VERSION 5.7 ;
  NOWIREEXTENSIONATPIN ON ;
  DIVIDERCHAR "/" ;
  BUSBITCHARS "[]" ;
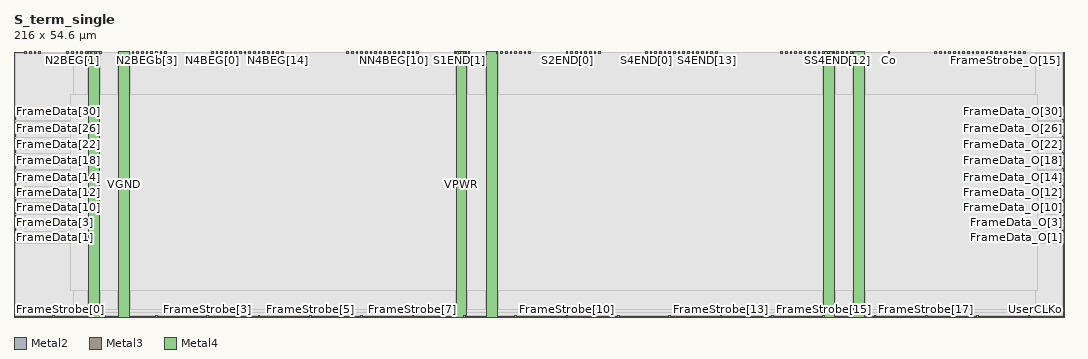
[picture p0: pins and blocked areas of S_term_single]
MACRO S_term_single
  CLASS BLOCK ;
  FOREIGN S_term_single ;
  ORIGIN 0.000 0.000 ;
  SIZE 216.000 BY 54.600 ;
  PIN Co
    DIRECTION OUTPUT ;
    USE SIGNAL ;
    ANTENNADIFFAREA 2.314600 ;
    PORT
      LAYER Metal2 ;
        RECT 179.800 54.200 180.200 54.600 ;
    END
  END Co
  PIN FrameData[0]
    DIRECTION INPUT ;
    USE SIGNAL ;
    ANTENNAGATEAREA 0.180700 ;
    ANTENNADIFFAREA 2.015400 ;
    PORT
      LAYER Metal3 ;
        RECT 0.000 15.340 0.400 15.740 ;
    END
  END FrameData[0]
  PIN FrameData[10]
    DIRECTION INPUT ;
    USE SIGNAL ;
    ANTENNAGATEAREA 0.180700 ;
    ANTENNADIFFAREA 2.015400 ;
    PORT
      LAYER Metal3 ;
        RECT 0.000 23.740 0.400 24.140 ;
    END
  END FrameData[10]
  PIN FrameData[11]
    DIRECTION INPUT ;
    USE SIGNAL ;
    ANTENNAGATEAREA 0.180700 ;
    ANTENNADIFFAREA 2.015400 ;
    PORT
      LAYER Metal3 ;
        RECT 0.000 24.580 0.400 24.980 ;
    END
  END FrameData[11]
  PIN FrameData[12]
    DIRECTION INPUT ;
    USE SIGNAL ;
    ANTENNAGATEAREA 0.180700 ;
    ANTENNADIFFAREA 2.015400 ;
    PORT
      LAYER Metal3 ;
        RECT 0.000 25.420 0.400 25.820 ;
    END
  END FrameData[12]
  PIN FrameData[13]
    DIRECTION INPUT ;
    USE SIGNAL ;
    ANTENNAGATEAREA 0.180700 ;
    ANTENNADIFFAREA 2.015400 ;
    PORT
      LAYER Metal3 ;
        RECT 0.000 26.260 0.400 26.660 ;
    END
  END FrameData[13]
  PIN FrameData[14]
    DIRECTION INPUT ;
    USE SIGNAL ;
    ANTENNAGATEAREA 0.180700 ;
    ANTENNADIFFAREA 2.015400 ;
    PORT
      LAYER Metal3 ;
        RECT 0.000 27.100 0.400 27.500 ;
    END
  END FrameData[14]
  PIN FrameData[15]
    DIRECTION INPUT ;
    USE SIGNAL ;
    ANTENNAGATEAREA 0.180700 ;
    ANTENNADIFFAREA 2.015400 ;
    PORT
      LAYER Metal3 ;
        RECT 0.000 27.940 0.400 28.340 ;
    END
  END FrameData[15]
  PIN FrameData[16]
    DIRECTION INPUT ;
    USE SIGNAL ;
    ANTENNAGATEAREA 0.180700 ;
    ANTENNADIFFAREA 2.015400 ;
    PORT
      LAYER Metal3 ;
        RECT 0.000 28.780 0.400 29.180 ;
    END
  END FrameData[16]
  PIN FrameData[17]
    DIRECTION INPUT ;
    USE SIGNAL ;
    ANTENNAGATEAREA 0.180700 ;
    ANTENNADIFFAREA 2.015400 ;
    PORT
      LAYER Metal3 ;
        RECT 0.000 29.620 0.400 30.020 ;
    END
  END FrameData[17]
  PIN FrameData[18]
    DIRECTION INPUT ;
    USE SIGNAL ;
    ANTENNAGATEAREA 0.180700 ;
    ANTENNADIFFAREA 2.015400 ;
    PORT
      LAYER Metal3 ;
        RECT 0.000 30.460 0.400 30.860 ;
    END
  END FrameData[18]
  PIN FrameData[19]
    DIRECTION INPUT ;
    USE SIGNAL ;
    ANTENNAGATEAREA 0.180700 ;
    ANTENNADIFFAREA 2.015400 ;
    PORT
      LAYER Metal3 ;
        RECT 0.000 31.300 0.400 31.700 ;
    END
  END FrameData[19]
  PIN FrameData[1]
    DIRECTION INPUT ;
    USE SIGNAL ;
    ANTENNAGATEAREA 0.180700 ;
    ANTENNADIFFAREA 2.015400 ;
    PORT
      LAYER Metal3 ;
        RECT 0.000 16.180 0.400 16.580 ;
    END
  END FrameData[1]
  PIN FrameData[20]
    DIRECTION INPUT ;
    USE SIGNAL ;
    ANTENNAGATEAREA 0.180700 ;
    ANTENNADIFFAREA 2.015400 ;
    PORT
      LAYER Metal3 ;
        RECT 0.000 32.140 0.400 32.540 ;
    END
  END FrameData[20]
  PIN FrameData[21]
    DIRECTION INPUT ;
    USE SIGNAL ;
    ANTENNAGATEAREA 0.180700 ;
    ANTENNADIFFAREA 2.015400 ;
    PORT
      LAYER Metal3 ;
        RECT 0.000 32.980 0.400 33.380 ;
    END
  END FrameData[21]
  PIN FrameData[22]
    DIRECTION INPUT ;
    USE SIGNAL ;
    ANTENNAGATEAREA 0.180700 ;
    ANTENNADIFFAREA 2.015400 ;
    PORT
      LAYER Metal3 ;
        RECT 0.000 33.820 0.400 34.220 ;
    END
  END FrameData[22]
  PIN FrameData[23]
    DIRECTION INPUT ;
    USE SIGNAL ;
    ANTENNAGATEAREA 0.180700 ;
    ANTENNADIFFAREA 2.015400 ;
    PORT
      LAYER Metal3 ;
        RECT 0.000 34.660 0.400 35.060 ;
    END
  END FrameData[23]
  PIN FrameData[24]
    DIRECTION INPUT ;
    USE SIGNAL ;
    ANTENNAGATEAREA 0.180700 ;
    ANTENNADIFFAREA 2.015400 ;
    PORT
      LAYER Metal3 ;
        RECT 0.000 35.500 0.400 35.900 ;
    END
  END FrameData[24]
  PIN FrameData[25]
    DIRECTION INPUT ;
    USE SIGNAL ;
    ANTENNAGATEAREA 0.180700 ;
    ANTENNADIFFAREA 2.015400 ;
    PORT
      LAYER Metal3 ;
        RECT 0.000 36.340 0.400 36.740 ;
    END
  END FrameData[25]
  PIN FrameData[26]
    DIRECTION INPUT ;
    USE SIGNAL ;
    ANTENNAGATEAREA 0.180700 ;
    ANTENNADIFFAREA 2.015400 ;
    PORT
      LAYER Metal3 ;
        RECT 0.000 37.180 0.400 37.580 ;
    END
  END FrameData[26]
  PIN FrameData[27]
    DIRECTION INPUT ;
    USE SIGNAL ;
    ANTENNAGATEAREA 0.180700 ;
    ANTENNADIFFAREA 2.015400 ;
    PORT
      LAYER Metal3 ;
        RECT 0.000 38.020 0.400 38.420 ;
    END
  END FrameData[27]
  PIN FrameData[28]
    DIRECTION INPUT ;
    USE SIGNAL ;
    ANTENNAGATEAREA 0.180700 ;
    ANTENNADIFFAREA 2.015400 ;
    PORT
      LAYER Metal3 ;
        RECT 0.000 38.860 0.400 39.260 ;
    END
  END FrameData[28]
  PIN FrameData[29]
    DIRECTION INPUT ;
    USE SIGNAL ;
    ANTENNAGATEAREA 0.180700 ;
    ANTENNADIFFAREA 2.015400 ;
    PORT
      LAYER Metal3 ;
        RECT 0.000 39.700 0.400 40.100 ;
    END
  END FrameData[29]
  PIN FrameData[2]
    DIRECTION INPUT ;
    USE SIGNAL ;
    ANTENNAGATEAREA 0.180700 ;
    ANTENNADIFFAREA 2.015400 ;
    PORT
      LAYER Metal3 ;
        RECT 0.000 17.020 0.400 17.420 ;
    END
  END FrameData[2]
  PIN FrameData[30]
    DIRECTION INPUT ;
    USE SIGNAL ;
    ANTENNAGATEAREA 0.180700 ;
    ANTENNADIFFAREA 2.015400 ;
    PORT
      LAYER Metal3 ;
        RECT 0.000 40.540 0.400 40.940 ;
    END
  END FrameData[30]
  PIN FrameData[31]
    DIRECTION INPUT ;
    USE SIGNAL ;
    ANTENNAGATEAREA 0.180700 ;
    ANTENNADIFFAREA 2.015400 ;
    PORT
      LAYER Metal3 ;
        RECT 0.000 41.380 0.400 41.780 ;
    END
  END FrameData[31]
  PIN FrameData[3]
    DIRECTION INPUT ;
    USE SIGNAL ;
    ANTENNAGATEAREA 0.180700 ;
    ANTENNADIFFAREA 2.015400 ;
    PORT
      LAYER Metal3 ;
        RECT 0.000 17.860 0.400 18.260 ;
    END
  END FrameData[3]
  PIN FrameData[4]
    DIRECTION INPUT ;
    USE SIGNAL ;
    ANTENNAGATEAREA 0.180700 ;
    ANTENNADIFFAREA 2.015400 ;
    PORT
      LAYER Metal3 ;
        RECT 0.000 18.700 0.400 19.100 ;
    END
  END FrameData[4]
  PIN FrameData[5]
    DIRECTION INPUT ;
    USE SIGNAL ;
    ANTENNAGATEAREA 0.180700 ;
    ANTENNADIFFAREA 2.015400 ;
    PORT
      LAYER Metal3 ;
        RECT 0.000 19.540 0.400 19.940 ;
    END
  END FrameData[5]
  PIN FrameData[6]
    DIRECTION INPUT ;
    USE SIGNAL ;
    ANTENNAGATEAREA 0.180700 ;
    ANTENNADIFFAREA 2.015400 ;
    PORT
      LAYER Metal3 ;
        RECT 0.000 20.380 0.400 20.780 ;
    END
  END FrameData[6]
  PIN FrameData[7]
    DIRECTION INPUT ;
    USE SIGNAL ;
    ANTENNAGATEAREA 0.180700 ;
    ANTENNADIFFAREA 2.015400 ;
    PORT
      LAYER Metal3 ;
        RECT 0.000 21.220 0.400 21.620 ;
    END
  END FrameData[7]
  PIN FrameData[8]
    DIRECTION INPUT ;
    USE SIGNAL ;
    ANTENNAGATEAREA 0.180700 ;
    ANTENNADIFFAREA 2.015400 ;
    PORT
      LAYER Metal3 ;
        RECT 0.000 22.060 0.400 22.460 ;
    END
  END FrameData[8]
  PIN FrameData[9]
    DIRECTION INPUT ;
    USE SIGNAL ;
    ANTENNAGATEAREA 0.180700 ;
    ANTENNADIFFAREA 2.015400 ;
    PORT
      LAYER Metal3 ;
        RECT 0.000 22.900 0.400 23.300 ;
    END
  END FrameData[9]
  PIN FrameData_O[0]
    DIRECTION OUTPUT ;
    USE SIGNAL ;
    ANTENNADIFFAREA 2.724000 ;
    PORT
      LAYER Metal3 ;
        RECT 215.600 15.340 216.000 15.740 ;
    END
  END FrameData_O[0]
  PIN FrameData_O[10]
    DIRECTION OUTPUT ;
    USE SIGNAL ;
    ANTENNADIFFAREA 2.724000 ;
    PORT
      LAYER Metal3 ;
        RECT 215.600 23.740 216.000 24.140 ;
    END
  END FrameData_O[10]
  PIN FrameData_O[11]
    DIRECTION OUTPUT ;
    USE SIGNAL ;
    ANTENNADIFFAREA 2.724000 ;
    PORT
      LAYER Metal3 ;
        RECT 215.600 24.580 216.000 24.980 ;
    END
  END FrameData_O[11]
  PIN FrameData_O[12]
    DIRECTION OUTPUT ;
    USE SIGNAL ;
    ANTENNADIFFAREA 2.724000 ;
    PORT
      LAYER Metal3 ;
        RECT 215.600 25.420 216.000 25.820 ;
    END
  END FrameData_O[12]
  PIN FrameData_O[13]
    DIRECTION OUTPUT ;
    USE SIGNAL ;
    ANTENNADIFFAREA 2.724000 ;
    PORT
      LAYER Metal3 ;
        RECT 215.600 26.260 216.000 26.660 ;
    END
  END FrameData_O[13]
  PIN FrameData_O[14]
    DIRECTION OUTPUT ;
    USE SIGNAL ;
    ANTENNADIFFAREA 2.724000 ;
    PORT
      LAYER Metal3 ;
        RECT 215.600 27.100 216.000 27.500 ;
    END
  END FrameData_O[14]
  PIN FrameData_O[15]
    DIRECTION OUTPUT ;
    USE SIGNAL ;
    ANTENNADIFFAREA 2.724000 ;
    PORT
      LAYER Metal3 ;
        RECT 215.600 27.940 216.000 28.340 ;
    END
  END FrameData_O[15]
  PIN FrameData_O[16]
    DIRECTION OUTPUT ;
    USE SIGNAL ;
    ANTENNADIFFAREA 2.724000 ;
    PORT
      LAYER Metal3 ;
        RECT 215.600 28.780 216.000 29.180 ;
    END
  END FrameData_O[16]
  PIN FrameData_O[17]
    DIRECTION OUTPUT ;
    USE SIGNAL ;
    ANTENNADIFFAREA 2.724000 ;
    PORT
      LAYER Metal3 ;
        RECT 215.600 29.620 216.000 30.020 ;
    END
  END FrameData_O[17]
  PIN FrameData_O[18]
    DIRECTION OUTPUT ;
    USE SIGNAL ;
    ANTENNADIFFAREA 2.724000 ;
    PORT
      LAYER Metal3 ;
        RECT 215.600 30.460 216.000 30.860 ;
    END
  END FrameData_O[18]
  PIN FrameData_O[19]
    DIRECTION OUTPUT ;
    USE SIGNAL ;
    ANTENNADIFFAREA 2.724000 ;
    PORT
      LAYER Metal3 ;
        RECT 215.600 31.300 216.000 31.700 ;
    END
  END FrameData_O[19]
  PIN FrameData_O[1]
    DIRECTION OUTPUT ;
    USE SIGNAL ;
    ANTENNADIFFAREA 2.724000 ;
    PORT
      LAYER Metal3 ;
        RECT 215.600 16.180 216.000 16.580 ;
    END
  END FrameData_O[1]
  PIN FrameData_O[20]
    DIRECTION OUTPUT ;
    USE SIGNAL ;
    ANTENNADIFFAREA 2.724000 ;
    PORT
      LAYER Metal3 ;
        RECT 215.600 32.140 216.000 32.540 ;
    END
  END FrameData_O[20]
  PIN FrameData_O[21]
    DIRECTION OUTPUT ;
    USE SIGNAL ;
    ANTENNADIFFAREA 2.724000 ;
    PORT
      LAYER Metal3 ;
        RECT 215.600 32.980 216.000 33.380 ;
    END
  END FrameData_O[21]
  PIN FrameData_O[22]
    DIRECTION OUTPUT ;
    USE SIGNAL ;
    ANTENNADIFFAREA 2.724000 ;
    PORT
      LAYER Metal3 ;
        RECT 215.600 33.820 216.000 34.220 ;
    END
  END FrameData_O[22]
  PIN FrameData_O[23]
    DIRECTION OUTPUT ;
    USE SIGNAL ;
    ANTENNADIFFAREA 2.724000 ;
    PORT
      LAYER Metal3 ;
        RECT 215.600 34.660 216.000 35.060 ;
    END
  END FrameData_O[23]
  PIN FrameData_O[24]
    DIRECTION OUTPUT ;
    USE SIGNAL ;
    ANTENNADIFFAREA 2.724000 ;
    PORT
      LAYER Metal3 ;
        RECT 215.600 35.500 216.000 35.900 ;
    END
  END FrameData_O[24]
  PIN FrameData_O[25]
    DIRECTION OUTPUT ;
    USE SIGNAL ;
    ANTENNADIFFAREA 2.724000 ;
    PORT
      LAYER Metal3 ;
        RECT 215.600 36.340 216.000 36.740 ;
    END
  END FrameData_O[25]
  PIN FrameData_O[26]
    DIRECTION OUTPUT ;
    USE SIGNAL ;
    ANTENNADIFFAREA 2.724000 ;
    PORT
      LAYER Metal3 ;
        RECT 215.600 37.180 216.000 37.580 ;
    END
  END FrameData_O[26]
  PIN FrameData_O[27]
    DIRECTION OUTPUT ;
    USE SIGNAL ;
    ANTENNADIFFAREA 2.724000 ;
    PORT
      LAYER Metal3 ;
        RECT 215.600 38.020 216.000 38.420 ;
    END
  END FrameData_O[27]
  PIN FrameData_O[28]
    DIRECTION OUTPUT ;
    USE SIGNAL ;
    ANTENNADIFFAREA 2.724000 ;
    PORT
      LAYER Metal3 ;
        RECT 215.600 38.860 216.000 39.260 ;
    END
  END FrameData_O[28]
  PIN FrameData_O[29]
    DIRECTION OUTPUT ;
    USE SIGNAL ;
    ANTENNADIFFAREA 2.724000 ;
    PORT
      LAYER Metal3 ;
        RECT 215.600 39.700 216.000 40.100 ;
    END
  END FrameData_O[29]
  PIN FrameData_O[2]
    DIRECTION OUTPUT ;
    USE SIGNAL ;
    ANTENNADIFFAREA 2.724000 ;
    PORT
      LAYER Metal3 ;
        RECT 215.600 17.020 216.000 17.420 ;
    END
  END FrameData_O[2]
  PIN FrameData_O[30]
    DIRECTION OUTPUT ;
    USE SIGNAL ;
    ANTENNADIFFAREA 2.724000 ;
    PORT
      LAYER Metal3 ;
        RECT 215.600 40.540 216.000 40.940 ;
    END
  END FrameData_O[30]
  PIN FrameData_O[31]
    DIRECTION OUTPUT ;
    USE SIGNAL ;
    ANTENNADIFFAREA 2.724000 ;
    PORT
      LAYER Metal3 ;
        RECT 215.600 41.380 216.000 41.780 ;
    END
  END FrameData_O[31]
  PIN FrameData_O[3]
    DIRECTION OUTPUT ;
    USE SIGNAL ;
    ANTENNADIFFAREA 2.724000 ;
    PORT
      LAYER Metal3 ;
        RECT 215.600 17.860 216.000 18.260 ;
    END
  END FrameData_O[3]
  PIN FrameData_O[4]
    DIRECTION OUTPUT ;
    USE SIGNAL ;
    ANTENNADIFFAREA 2.724000 ;
    PORT
      LAYER Metal3 ;
        RECT 215.600 18.700 216.000 19.100 ;
    END
  END FrameData_O[4]
  PIN FrameData_O[5]
    DIRECTION OUTPUT ;
    USE SIGNAL ;
    ANTENNADIFFAREA 2.724000 ;
    PORT
      LAYER Metal3 ;
        RECT 215.600 19.540 216.000 19.940 ;
    END
  END FrameData_O[5]
  PIN FrameData_O[6]
    DIRECTION OUTPUT ;
    USE SIGNAL ;
    ANTENNADIFFAREA 2.724000 ;
    PORT
      LAYER Metal3 ;
        RECT 215.600 20.380 216.000 20.780 ;
    END
  END FrameData_O[6]
  PIN FrameData_O[7]
    DIRECTION OUTPUT ;
    USE SIGNAL ;
    ANTENNADIFFAREA 2.724000 ;
    PORT
      LAYER Metal3 ;
        RECT 215.600 21.220 216.000 21.620 ;
    END
  END FrameData_O[7]
  PIN FrameData_O[8]
    DIRECTION OUTPUT ;
    USE SIGNAL ;
    ANTENNADIFFAREA 2.724000 ;
    PORT
      LAYER Metal3 ;
        RECT 215.600 22.060 216.000 22.460 ;
    END
  END FrameData_O[8]
  PIN FrameData_O[9]
    DIRECTION OUTPUT ;
    USE SIGNAL ;
    ANTENNADIFFAREA 2.724000 ;
    PORT
      LAYER Metal3 ;
        RECT 215.600 22.900 216.000 23.300 ;
    END
  END FrameData_O[9]
  PIN FrameStrobe[0]
    DIRECTION INPUT ;
    USE SIGNAL ;
    ANTENNAGATEAREA 0.180700 ;
    ANTENNADIFFAREA 2.015400 ;
    PORT
      LAYER Metal2 ;
        RECT 7.960 0.000 8.360 0.400 ;
    END
  END FrameStrobe[0]
  PIN FrameStrobe[10]
    DIRECTION INPUT ;
    USE SIGNAL ;
    ANTENNAGATEAREA 0.180700 ;
    ANTENNADIFFAREA 2.015400 ;
    PORT
      LAYER Metal2 ;
        RECT 113.560 0.000 113.960 0.400 ;
    END
  END FrameStrobe[10]
  PIN FrameStrobe[11]
    DIRECTION INPUT ;
    USE SIGNAL ;
    ANTENNAGATEAREA 0.180700 ;
    ANTENNADIFFAREA 2.015400 ;
    PORT
      LAYER Metal2 ;
        RECT 124.120 0.000 124.520 0.400 ;
    END
  END FrameStrobe[11]
  PIN FrameStrobe[12]
    DIRECTION INPUT ;
    USE SIGNAL ;
    ANTENNAGATEAREA 0.180700 ;
    ANTENNADIFFAREA 2.015400 ;
    PORT
      LAYER Metal2 ;
        RECT 134.680 0.000 135.080 0.400 ;
    END
  END FrameStrobe[12]
  PIN FrameStrobe[13]
    DIRECTION INPUT ;
    USE SIGNAL ;
    ANTENNAGATEAREA 0.180700 ;
    ANTENNADIFFAREA 2.015400 ;
    PORT
      LAYER Metal2 ;
        RECT 145.240 0.000 145.640 0.400 ;
    END
  END FrameStrobe[13]
  PIN FrameStrobe[14]
    DIRECTION INPUT ;
    USE SIGNAL ;
    ANTENNAGATEAREA 0.180700 ;
    ANTENNADIFFAREA 2.015400 ;
    PORT
      LAYER Metal2 ;
        RECT 155.800 0.000 156.200 0.400 ;
    END
  END FrameStrobe[14]
  PIN FrameStrobe[15]
    DIRECTION INPUT ;
    USE SIGNAL ;
    ANTENNAGATEAREA 0.180700 ;
    ANTENNADIFFAREA 2.015400 ;
    PORT
      LAYER Metal2 ;
        RECT 166.360 0.000 166.760 0.400 ;
    END
  END FrameStrobe[15]
  PIN FrameStrobe[16]
    DIRECTION INPUT ;
    USE SIGNAL ;
    ANTENNAGATEAREA 0.180700 ;
    ANTENNADIFFAREA 2.015400 ;
    PORT
      LAYER Metal2 ;
        RECT 176.920 0.000 177.320 0.400 ;
    END
  END FrameStrobe[16]
  PIN FrameStrobe[17]
    DIRECTION INPUT ;
    USE SIGNAL ;
    ANTENNAGATEAREA 0.180700 ;
    ANTENNADIFFAREA 2.015400 ;
    PORT
      LAYER Metal2 ;
        RECT 187.480 0.000 187.880 0.400 ;
    END
  END FrameStrobe[17]
  PIN FrameStrobe[18]
    DIRECTION INPUT ;
    USE SIGNAL ;
    ANTENNAGATEAREA 0.180700 ;
    ANTENNADIFFAREA 2.015400 ;
    PORT
      LAYER Metal2 ;
        RECT 198.040 0.000 198.440 0.400 ;
    END
  END FrameStrobe[18]
  PIN FrameStrobe[19]
    DIRECTION INPUT ;
    USE SIGNAL ;
    ANTENNAGATEAREA 0.180700 ;
    ANTENNADIFFAREA 2.015400 ;
    PORT
      LAYER Metal2 ;
        RECT 208.600 0.000 209.000 0.400 ;
    END
  END FrameStrobe[19]
  PIN FrameStrobe[1]
    DIRECTION INPUT ;
    USE SIGNAL ;
    ANTENNAGATEAREA 0.180700 ;
    ANTENNADIFFAREA 2.015400 ;
    PORT
      LAYER Metal2 ;
        RECT 18.520 0.000 18.920 0.400 ;
    END
  END FrameStrobe[1]
  PIN FrameStrobe[2]
    DIRECTION INPUT ;
    USE SIGNAL ;
    ANTENNAGATEAREA 0.180700 ;
    ANTENNADIFFAREA 2.015400 ;
    PORT
      LAYER Metal2 ;
        RECT 29.080 0.000 29.480 0.400 ;
    END
  END FrameStrobe[2]
  PIN FrameStrobe[3]
    DIRECTION INPUT ;
    USE SIGNAL ;
    ANTENNAGATEAREA 0.180700 ;
    ANTENNADIFFAREA 2.015400 ;
    PORT
      LAYER Metal2 ;
        RECT 39.640 0.000 40.040 0.400 ;
    END
  END FrameStrobe[3]
  PIN FrameStrobe[4]
    DIRECTION INPUT ;
    USE SIGNAL ;
    ANTENNAGATEAREA 0.180700 ;
    ANTENNADIFFAREA 2.015400 ;
    PORT
      LAYER Metal2 ;
        RECT 50.200 0.000 50.600 0.400 ;
    END
  END FrameStrobe[4]
  PIN FrameStrobe[5]
    DIRECTION INPUT ;
    USE SIGNAL ;
    ANTENNAGATEAREA 0.180700 ;
    ANTENNADIFFAREA 2.015400 ;
    PORT
      LAYER Metal2 ;
        RECT 60.760 0.000 61.160 0.400 ;
    END
  END FrameStrobe[5]
  PIN FrameStrobe[6]
    DIRECTION INPUT ;
    USE SIGNAL ;
    ANTENNAGATEAREA 0.180700 ;
    ANTENNADIFFAREA 2.015400 ;
    PORT
      LAYER Metal2 ;
        RECT 71.320 0.000 71.720 0.400 ;
    END
  END FrameStrobe[6]
  PIN FrameStrobe[7]
    DIRECTION INPUT ;
    USE SIGNAL ;
    ANTENNAGATEAREA 0.180700 ;
    ANTENNADIFFAREA 2.015400 ;
    PORT
      LAYER Metal2 ;
        RECT 81.880 0.000 82.280 0.400 ;
    END
  END FrameStrobe[7]
  PIN FrameStrobe[8]
    DIRECTION INPUT ;
    USE SIGNAL ;
    ANTENNAGATEAREA 0.180700 ;
    ANTENNADIFFAREA 2.015400 ;
    PORT
      LAYER Metal2 ;
        RECT 92.440 0.000 92.840 0.400 ;
    END
  END FrameStrobe[8]
  PIN FrameStrobe[9]
    DIRECTION INPUT ;
    USE SIGNAL ;
    ANTENNAGATEAREA 0.180700 ;
    ANTENNADIFFAREA 2.015400 ;
    PORT
      LAYER Metal2 ;
        RECT 103.000 0.000 103.400 0.400 ;
    END
  END FrameStrobe[9]
  PIN FrameStrobe_O[0]
    DIRECTION OUTPUT ;
    USE SIGNAL ;
    ANTENNADIFFAREA 2.724000 ;
    PORT
      LAYER Metal2 ;
        RECT 189.400 54.200 189.800 54.600 ;
    END
  END FrameStrobe_O[0]
  PIN FrameStrobe_O[10]
    DIRECTION OUTPUT ;
    USE SIGNAL ;
    ANTENNADIFFAREA 2.724000 ;
    PORT
      LAYER Metal2 ;
        RECT 199.000 54.200 199.400 54.600 ;
    END
  END FrameStrobe_O[10]
  PIN FrameStrobe_O[11]
    DIRECTION OUTPUT ;
    USE SIGNAL ;
    ANTENNADIFFAREA 2.724000 ;
    PORT
      LAYER Metal2 ;
        RECT 199.960 54.200 200.360 54.600 ;
    END
  END FrameStrobe_O[11]
  PIN FrameStrobe_O[12]
    DIRECTION OUTPUT ;
    USE SIGNAL ;
    ANTENNADIFFAREA 2.724000 ;
    PORT
      LAYER Metal2 ;
        RECT 200.920 54.200 201.320 54.600 ;
    END
  END FrameStrobe_O[12]
  PIN FrameStrobe_O[13]
    DIRECTION OUTPUT ;
    USE SIGNAL ;
    ANTENNADIFFAREA 2.724000 ;
    PORT
      LAYER Metal2 ;
        RECT 201.880 54.200 202.280 54.600 ;
    END
  END FrameStrobe_O[13]
  PIN FrameStrobe_O[14]
    DIRECTION OUTPUT ;
    USE SIGNAL ;
    ANTENNADIFFAREA 2.724000 ;
    PORT
      LAYER Metal2 ;
        RECT 202.840 54.200 203.240 54.600 ;
    END
  END FrameStrobe_O[14]
  PIN FrameStrobe_O[15]
    DIRECTION OUTPUT ;
    USE SIGNAL ;
    ANTENNADIFFAREA 2.724000 ;
    PORT
      LAYER Metal2 ;
        RECT 203.800 54.200 204.200 54.600 ;
    END
  END FrameStrobe_O[15]
  PIN FrameStrobe_O[16]
    DIRECTION OUTPUT ;
    USE SIGNAL ;
    ANTENNADIFFAREA 2.724000 ;
    PORT
      LAYER Metal2 ;
        RECT 204.760 54.200 205.160 54.600 ;
    END
  END FrameStrobe_O[16]
  PIN FrameStrobe_O[17]
    DIRECTION OUTPUT ;
    USE SIGNAL ;
    ANTENNADIFFAREA 2.724000 ;
    PORT
      LAYER Metal2 ;
        RECT 205.720 54.200 206.120 54.600 ;
    END
  END FrameStrobe_O[17]
  PIN FrameStrobe_O[18]
    DIRECTION OUTPUT ;
    USE SIGNAL ;
    ANTENNADIFFAREA 2.724000 ;
    PORT
      LAYER Metal2 ;
        RECT 206.680 54.200 207.080 54.600 ;
    END
  END FrameStrobe_O[18]
  PIN FrameStrobe_O[19]
    DIRECTION OUTPUT ;
    USE SIGNAL ;
    ANTENNADIFFAREA 2.724000 ;
    PORT
      LAYER Metal2 ;
        RECT 207.640 54.200 208.040 54.600 ;
    END
  END FrameStrobe_O[19]
  PIN FrameStrobe_O[1]
    DIRECTION OUTPUT ;
    USE SIGNAL ;
    ANTENNADIFFAREA 2.724000 ;
    PORT
      LAYER Metal2 ;
        RECT 190.360 54.200 190.760 54.600 ;
    END
  END FrameStrobe_O[1]
  PIN FrameStrobe_O[2]
    DIRECTION OUTPUT ;
    USE SIGNAL ;
    ANTENNADIFFAREA 2.724000 ;
    PORT
      LAYER Metal2 ;
        RECT 191.320 54.200 191.720 54.600 ;
    END
  END FrameStrobe_O[2]
  PIN FrameStrobe_O[3]
    DIRECTION OUTPUT ;
    USE SIGNAL ;
    ANTENNADIFFAREA 2.724000 ;
    PORT
      LAYER Metal2 ;
        RECT 192.280 54.200 192.680 54.600 ;
    END
  END FrameStrobe_O[3]
  PIN FrameStrobe_O[4]
    DIRECTION OUTPUT ;
    USE SIGNAL ;
    ANTENNADIFFAREA 2.724000 ;
    PORT
      LAYER Metal2 ;
        RECT 193.240 54.200 193.640 54.600 ;
    END
  END FrameStrobe_O[4]
  PIN FrameStrobe_O[5]
    DIRECTION OUTPUT ;
    USE SIGNAL ;
    ANTENNADIFFAREA 2.724000 ;
    PORT
      LAYER Metal2 ;
        RECT 194.200 54.200 194.600 54.600 ;
    END
  END FrameStrobe_O[5]
  PIN FrameStrobe_O[6]
    DIRECTION OUTPUT ;
    USE SIGNAL ;
    ANTENNADIFFAREA 2.724000 ;
    PORT
      LAYER Metal2 ;
        RECT 195.160 54.200 195.560 54.600 ;
    END
  END FrameStrobe_O[6]
  PIN FrameStrobe_O[7]
    DIRECTION OUTPUT ;
    USE SIGNAL ;
    ANTENNADIFFAREA 2.724000 ;
    PORT
      LAYER Metal2 ;
        RECT 196.120 54.200 196.520 54.600 ;
    END
  END FrameStrobe_O[7]
  PIN FrameStrobe_O[8]
    DIRECTION OUTPUT ;
    USE SIGNAL ;
    ANTENNADIFFAREA 2.724000 ;
    PORT
      LAYER Metal2 ;
        RECT 197.080 54.200 197.480 54.600 ;
    END
  END FrameStrobe_O[8]
  PIN FrameStrobe_O[9]
    DIRECTION OUTPUT ;
    USE SIGNAL ;
    ANTENNADIFFAREA 2.724000 ;
    PORT
      LAYER Metal2 ;
        RECT 198.040 54.200 198.440 54.600 ;
    END
  END FrameStrobe_O[9]
  PIN N1BEG[0]
    DIRECTION OUTPUT ;
    USE SIGNAL ;
    ANTENNADIFFAREA 2.724000 ;
    PORT
      LAYER Metal2 ;
        RECT 2.200 54.200 2.600 54.600 ;
    END
  END N1BEG[0]
  PIN N1BEG[1]
    DIRECTION OUTPUT ;
    USE SIGNAL ;
    ANTENNADIFFAREA 2.724000 ;
    PORT
      LAYER Metal2 ;
        RECT 3.160 54.200 3.560 54.600 ;
    END
  END N1BEG[1]
  PIN N1BEG[2]
    DIRECTION OUTPUT ;
    USE SIGNAL ;
    ANTENNADIFFAREA 2.724000 ;
    PORT
      LAYER Metal2 ;
        RECT 4.120 54.200 4.520 54.600 ;
    END
  END N1BEG[2]
  PIN N1BEG[3]
    DIRECTION OUTPUT ;
    USE SIGNAL ;
    ANTENNADIFFAREA 2.724000 ;
    PORT
      LAYER Metal2 ;
        RECT 5.080 54.200 5.480 54.600 ;
    END
  END N1BEG[3]
  PIN N2BEG[0]
    DIRECTION OUTPUT ;
    USE SIGNAL ;
    ANTENNADIFFAREA 2.724000 ;
    PORT
      LAYER Metal2 ;
        RECT 10.840 54.200 11.240 54.600 ;
    END
  END N2BEG[0]
  PIN N2BEG[1]
    DIRECTION OUTPUT ;
    USE SIGNAL ;
    ANTENNADIFFAREA 2.724000 ;
    PORT
      LAYER Metal2 ;
        RECT 11.800 54.200 12.200 54.600 ;
    END
  END N2BEG[1]
  PIN N2BEG[2]
    DIRECTION OUTPUT ;
    USE SIGNAL ;
    ANTENNADIFFAREA 2.724000 ;
    PORT
      LAYER Metal2 ;
        RECT 12.760 54.200 13.160 54.600 ;
    END
  END N2BEG[2]
  PIN N2BEG[3]
    DIRECTION OUTPUT ;
    USE SIGNAL ;
    ANTENNADIFFAREA 2.724000 ;
    PORT
      LAYER Metal2 ;
        RECT 13.720 54.200 14.120 54.600 ;
    END
  END N2BEG[3]
  PIN N2BEG[4]
    DIRECTION OUTPUT ;
    USE SIGNAL ;
    ANTENNADIFFAREA 2.724000 ;
    PORT
      LAYER Metal2 ;
        RECT 14.680 54.200 15.080 54.600 ;
    END
  END N2BEG[4]
  PIN N2BEG[5]
    DIRECTION OUTPUT ;
    USE SIGNAL ;
    ANTENNADIFFAREA 2.724000 ;
    PORT
      LAYER Metal2 ;
        RECT 15.640 54.200 16.040 54.600 ;
    END
  END N2BEG[5]
  PIN N2BEG[6]
    DIRECTION OUTPUT ;
    USE SIGNAL ;
    ANTENNADIFFAREA 2.724000 ;
    PORT
      LAYER Metal2 ;
        RECT 16.600 54.200 17.000 54.600 ;
    END
  END N2BEG[6]
  PIN N2BEG[7]
    DIRECTION OUTPUT ;
    USE SIGNAL ;
    ANTENNADIFFAREA 2.724000 ;
    PORT
      LAYER Metal2 ;
        RECT 17.560 54.200 17.960 54.600 ;
    END
  END N2BEG[7]
  PIN N2BEGb[0]
    DIRECTION OUTPUT ;
    USE SIGNAL ;
    ANTENNADIFFAREA 2.724000 ;
    PORT
      LAYER Metal2 ;
        RECT 24.280 54.200 24.680 54.600 ;
    END
  END N2BEGb[0]
  PIN N2BEGb[1]
    DIRECTION OUTPUT ;
    USE SIGNAL ;
    ANTENNADIFFAREA 2.724000 ;
    PORT
      LAYER Metal2 ;
        RECT 25.240 54.200 25.640 54.600 ;
    END
  END N2BEGb[1]
  PIN N2BEGb[2]
    DIRECTION OUTPUT ;
    USE SIGNAL ;
    ANTENNADIFFAREA 2.724000 ;
    PORT
      LAYER Metal2 ;
        RECT 26.200 54.200 26.600 54.600 ;
    END
  END N2BEGb[2]
  PIN N2BEGb[3]
    DIRECTION OUTPUT ;
    USE SIGNAL ;
    ANTENNADIFFAREA 2.724000 ;
    PORT
      LAYER Metal2 ;
        RECT 27.160 54.200 27.560 54.600 ;
    END
  END N2BEGb[3]
  PIN N2BEGb[4]
    DIRECTION OUTPUT ;
    USE SIGNAL ;
    ANTENNADIFFAREA 2.724000 ;
    PORT
      LAYER Metal2 ;
        RECT 28.120 54.200 28.520 54.600 ;
    END
  END N2BEGb[4]
  PIN N2BEGb[5]
    DIRECTION OUTPUT ;
    USE SIGNAL ;
    ANTENNADIFFAREA 2.724000 ;
    PORT
      LAYER Metal2 ;
        RECT 29.080 54.200 29.480 54.600 ;
    END
  END N2BEGb[5]
  PIN N2BEGb[6]
    DIRECTION OUTPUT ;
    USE SIGNAL ;
    ANTENNADIFFAREA 2.724000 ;
    PORT
      LAYER Metal2 ;
        RECT 30.040 54.200 30.440 54.600 ;
    END
  END N2BEGb[6]
  PIN N2BEGb[7]
    DIRECTION OUTPUT ;
    USE SIGNAL ;
    ANTENNADIFFAREA 2.724000 ;
    PORT
      LAYER Metal2 ;
        RECT 31.000 54.200 31.400 54.600 ;
    END
  END N2BEGb[7]
  PIN N4BEG[0]
    DIRECTION OUTPUT ;
    USE SIGNAL ;
    ANTENNADIFFAREA 2.724000 ;
    PORT
      LAYER Metal2 ;
        RECT 40.600 54.200 41.000 54.600 ;
    END
  END N4BEG[0]
  PIN N4BEG[10]
    DIRECTION OUTPUT ;
    USE SIGNAL ;
    ANTENNADIFFAREA 2.724000 ;
    PORT
      LAYER Metal2 ;
        RECT 50.200 54.200 50.600 54.600 ;
    END
  END N4BEG[10]
  PIN N4BEG[11]
    DIRECTION OUTPUT ;
    USE SIGNAL ;
    ANTENNADIFFAREA 2.724000 ;
    PORT
      LAYER Metal2 ;
        RECT 51.160 54.200 51.560 54.600 ;
    END
  END N4BEG[11]
  PIN N4BEG[12]
    DIRECTION OUTPUT ;
    USE SIGNAL ;
    ANTENNADIFFAREA 2.724000 ;
    PORT
      LAYER Metal2 ;
        RECT 52.120 54.200 52.520 54.600 ;
    END
  END N4BEG[12]
  PIN N4BEG[13]
    DIRECTION OUTPUT ;
    USE SIGNAL ;
    ANTENNADIFFAREA 2.724000 ;
    PORT
      LAYER Metal2 ;
        RECT 53.080 54.200 53.480 54.600 ;
    END
  END N4BEG[13]
  PIN N4BEG[14]
    DIRECTION OUTPUT ;
    USE SIGNAL ;
    ANTENNADIFFAREA 2.724000 ;
    PORT
      LAYER Metal2 ;
        RECT 54.040 54.200 54.440 54.600 ;
    END
  END N4BEG[14]
  PIN N4BEG[15]
    DIRECTION OUTPUT ;
    USE SIGNAL ;
    ANTENNADIFFAREA 2.724000 ;
    PORT
      LAYER Metal2 ;
        RECT 55.000 54.200 55.400 54.600 ;
    END
  END N4BEG[15]
  PIN N4BEG[1]
    DIRECTION OUTPUT ;
    USE SIGNAL ;
    ANTENNADIFFAREA 2.724000 ;
    PORT
      LAYER Metal2 ;
        RECT 41.560 54.200 41.960 54.600 ;
    END
  END N4BEG[1]
  PIN N4BEG[2]
    DIRECTION OUTPUT ;
    USE SIGNAL ;
    ANTENNADIFFAREA 2.724000 ;
    PORT
      LAYER Metal2 ;
        RECT 42.520 54.200 42.920 54.600 ;
    END
  END N4BEG[2]
  PIN N4BEG[3]
    DIRECTION OUTPUT ;
    USE SIGNAL ;
    ANTENNADIFFAREA 2.724000 ;
    PORT
      LAYER Metal2 ;
        RECT 43.480 54.200 43.880 54.600 ;
    END
  END N4BEG[3]
  PIN N4BEG[4]
    DIRECTION OUTPUT ;
    USE SIGNAL ;
    ANTENNADIFFAREA 2.724000 ;
    PORT
      LAYER Metal2 ;
        RECT 44.440 54.200 44.840 54.600 ;
    END
  END N4BEG[4]
  PIN N4BEG[5]
    DIRECTION OUTPUT ;
    USE SIGNAL ;
    ANTENNADIFFAREA 2.724000 ;
    PORT
      LAYER Metal2 ;
        RECT 45.400 54.200 45.800 54.600 ;
    END
  END N4BEG[5]
  PIN N4BEG[6]
    DIRECTION OUTPUT ;
    USE SIGNAL ;
    ANTENNADIFFAREA 2.724000 ;
    PORT
      LAYER Metal2 ;
        RECT 46.360 54.200 46.760 54.600 ;
    END
  END N4BEG[6]
  PIN N4BEG[7]
    DIRECTION OUTPUT ;
    USE SIGNAL ;
    ANTENNADIFFAREA 2.724000 ;
    PORT
      LAYER Metal2 ;
        RECT 47.320 54.200 47.720 54.600 ;
    END
  END N4BEG[7]
  PIN N4BEG[8]
    DIRECTION OUTPUT ;
    USE SIGNAL ;
    ANTENNADIFFAREA 2.724000 ;
    PORT
      LAYER Metal2 ;
        RECT 48.280 54.200 48.680 54.600 ;
    END
  END N4BEG[8]
  PIN N4BEG[9]
    DIRECTION OUTPUT ;
    USE SIGNAL ;
    ANTENNADIFFAREA 2.724000 ;
    PORT
      LAYER Metal2 ;
        RECT 49.240 54.200 49.640 54.600 ;
    END
  END N4BEG[9]
  PIN NN4BEG[0]
    DIRECTION OUTPUT ;
    USE SIGNAL ;
    ANTENNADIFFAREA 2.724000 ;
    PORT
      LAYER Metal2 ;
        RECT 68.440 54.200 68.840 54.600 ;
    END
  END NN4BEG[0]
  PIN NN4BEG[10]
    DIRECTION OUTPUT ;
    USE SIGNAL ;
    ANTENNADIFFAREA 2.724000 ;
    PORT
      LAYER Metal2 ;
        RECT 78.040 54.200 78.440 54.600 ;
    END
  END NN4BEG[10]
  PIN NN4BEG[11]
    DIRECTION OUTPUT ;
    USE SIGNAL ;
    ANTENNADIFFAREA 2.724000 ;
    PORT
      LAYER Metal2 ;
        RECT 79.000 54.200 79.400 54.600 ;
    END
  END NN4BEG[11]
  PIN NN4BEG[12]
    DIRECTION OUTPUT ;
    USE SIGNAL ;
    ANTENNADIFFAREA 2.724000 ;
    PORT
      LAYER Metal2 ;
        RECT 79.960 54.200 80.360 54.600 ;
    END
  END NN4BEG[12]
  PIN NN4BEG[13]
    DIRECTION OUTPUT ;
    USE SIGNAL ;
    ANTENNADIFFAREA 2.724000 ;
    PORT
      LAYER Metal2 ;
        RECT 80.920 54.200 81.320 54.600 ;
    END
  END NN4BEG[13]
  PIN NN4BEG[14]
    DIRECTION OUTPUT ;
    USE SIGNAL ;
    ANTENNADIFFAREA 2.724000 ;
    PORT
      LAYER Metal2 ;
        RECT 81.880 54.200 82.280 54.600 ;
    END
  END NN4BEG[14]
  PIN NN4BEG[15]
    DIRECTION OUTPUT ;
    USE SIGNAL ;
    ANTENNADIFFAREA 2.724000 ;
    PORT
      LAYER Metal2 ;
        RECT 82.840 54.200 83.240 54.600 ;
    END
  END NN4BEG[15]
  PIN NN4BEG[1]
    DIRECTION OUTPUT ;
    USE SIGNAL ;
    ANTENNADIFFAREA 2.724000 ;
    PORT
      LAYER Metal2 ;
        RECT 69.400 54.200 69.800 54.600 ;
    END
  END NN4BEG[1]
  PIN NN4BEG[2]
    DIRECTION OUTPUT ;
    USE SIGNAL ;
    ANTENNADIFFAREA 2.724000 ;
    PORT
      LAYER Metal2 ;
        RECT 70.360 54.200 70.760 54.600 ;
    END
  END NN4BEG[2]
  PIN NN4BEG[3]
    DIRECTION OUTPUT ;
    USE SIGNAL ;
    ANTENNADIFFAREA 2.724000 ;
    PORT
      LAYER Metal2 ;
        RECT 71.320 54.200 71.720 54.600 ;
    END
  END NN4BEG[3]
  PIN NN4BEG[4]
    DIRECTION OUTPUT ;
    USE SIGNAL ;
    ANTENNADIFFAREA 2.724000 ;
    PORT
      LAYER Metal2 ;
        RECT 72.280 54.200 72.680 54.600 ;
    END
  END NN4BEG[4]
  PIN NN4BEG[5]
    DIRECTION OUTPUT ;
    USE SIGNAL ;
    ANTENNADIFFAREA 2.724000 ;
    PORT
      LAYER Metal2 ;
        RECT 73.240 54.200 73.640 54.600 ;
    END
  END NN4BEG[5]
  PIN NN4BEG[6]
    DIRECTION OUTPUT ;
    USE SIGNAL ;
    ANTENNADIFFAREA 2.724000 ;
    PORT
      LAYER Metal2 ;
        RECT 74.200 54.200 74.600 54.600 ;
    END
  END NN4BEG[6]
  PIN NN4BEG[7]
    DIRECTION OUTPUT ;
    USE SIGNAL ;
    ANTENNADIFFAREA 2.724000 ;
    PORT
      LAYER Metal2 ;
        RECT 75.160 54.200 75.560 54.600 ;
    END
  END NN4BEG[7]
  PIN NN4BEG[8]
    DIRECTION OUTPUT ;
    USE SIGNAL ;
    ANTENNADIFFAREA 2.724000 ;
    PORT
      LAYER Metal2 ;
        RECT 76.120 54.200 76.520 54.600 ;
    END
  END NN4BEG[8]
  PIN NN4BEG[9]
    DIRECTION OUTPUT ;
    USE SIGNAL ;
    ANTENNADIFFAREA 2.724000 ;
    PORT
      LAYER Metal2 ;
        RECT 77.080 54.200 77.480 54.600 ;
    END
  END NN4BEG[9]
  PIN S1END[0]
    DIRECTION INPUT ;
    USE SIGNAL ;
    ANTENNAGATEAREA 0.180700 ;
    ANTENNADIFFAREA 2.015400 ;
    PORT
      LAYER Metal2 ;
        RECT 90.520 54.200 90.920 54.600 ;
    END
  END S1END[0]
  PIN S1END[1]
    DIRECTION INPUT ;
    USE SIGNAL ;
    ANTENNAGATEAREA 0.180700 ;
    ANTENNADIFFAREA 2.015400 ;
    PORT
      LAYER Metal2 ;
        RECT 91.480 54.200 91.880 54.600 ;
    END
  END S1END[1]
  PIN S1END[2]
    DIRECTION INPUT ;
    USE SIGNAL ;
    ANTENNAGATEAREA 0.180700 ;
    ANTENNADIFFAREA 2.015400 ;
    PORT
      LAYER Metal2 ;
        RECT 92.440 54.200 92.840 54.600 ;
    END
  END S1END[2]
  PIN S1END[3]
    DIRECTION INPUT ;
    USE SIGNAL ;
    ANTENNAGATEAREA 0.180700 ;
    ANTENNADIFFAREA 2.015400 ;
    PORT
      LAYER Metal2 ;
        RECT 93.400 54.200 93.800 54.600 ;
    END
  END S1END[3]
  PIN S2END[0]
    DIRECTION INPUT ;
    USE SIGNAL ;
    ANTENNAGATEAREA 0.180700 ;
    ANTENNADIFFAREA 2.015400 ;
    PORT
      LAYER Metal2 ;
        RECT 113.560 54.200 113.960 54.600 ;
    END
  END S2END[0]
  PIN S2END[1]
    DIRECTION INPUT ;
    USE SIGNAL ;
    ANTENNAGATEAREA 0.180700 ;
    ANTENNADIFFAREA 2.015400 ;
    PORT
      LAYER Metal2 ;
        RECT 114.520 54.200 114.920 54.600 ;
    END
  END S2END[1]
  PIN S2END[2]
    DIRECTION INPUT ;
    USE SIGNAL ;
    ANTENNAGATEAREA 0.180700 ;
    ANTENNADIFFAREA 2.015400 ;
    PORT
      LAYER Metal2 ;
        RECT 115.480 54.200 115.880 54.600 ;
    END
  END S2END[2]
  PIN S2END[3]
    DIRECTION INPUT ;
    USE SIGNAL ;
    ANTENNAGATEAREA 0.180700 ;
    ANTENNADIFFAREA 2.015400 ;
    PORT
      LAYER Metal2 ;
        RECT 116.440 54.200 116.840 54.600 ;
    END
  END S2END[3]
  PIN S2END[4]
    DIRECTION INPUT ;
    USE SIGNAL ;
    ANTENNAGATEAREA 0.180700 ;
    ANTENNADIFFAREA 2.015400 ;
    PORT
      LAYER Metal2 ;
        RECT 117.400 54.200 117.800 54.600 ;
    END
  END S2END[4]
  PIN S2END[5]
    DIRECTION INPUT ;
    USE SIGNAL ;
    ANTENNAGATEAREA 0.180700 ;
    ANTENNADIFFAREA 2.015400 ;
    PORT
      LAYER Metal2 ;
        RECT 118.360 54.200 118.760 54.600 ;
    END
  END S2END[5]
  PIN S2END[6]
    DIRECTION INPUT ;
    USE SIGNAL ;
    ANTENNAGATEAREA 0.180700 ;
    ANTENNADIFFAREA 2.015400 ;
    PORT
      LAYER Metal2 ;
        RECT 119.320 54.200 119.720 54.600 ;
    END
  END S2END[6]
  PIN S2END[7]
    DIRECTION INPUT ;
    USE SIGNAL ;
    ANTENNAGATEAREA 0.180700 ;
    ANTENNADIFFAREA 2.015400 ;
    PORT
      LAYER Metal2 ;
        RECT 120.280 54.200 120.680 54.600 ;
    END
  END S2END[7]
  PIN S2MID[0]
    DIRECTION INPUT ;
    USE SIGNAL ;
    ANTENNAGATEAREA 0.180700 ;
    ANTENNADIFFAREA 2.015400 ;
    PORT
      LAYER Metal2 ;
        RECT 99.160 54.200 99.560 54.600 ;
    END
  END S2MID[0]
  PIN S2MID[1]
    DIRECTION INPUT ;
    USE SIGNAL ;
    ANTENNAGATEAREA 0.180700 ;
    ANTENNADIFFAREA 2.015400 ;
    PORT
      LAYER Metal2 ;
        RECT 100.120 54.200 100.520 54.600 ;
    END
  END S2MID[1]
  PIN S2MID[2]
    DIRECTION INPUT ;
    USE SIGNAL ;
    ANTENNAGATEAREA 0.180700 ;
    ANTENNADIFFAREA 2.015400 ;
    PORT
      LAYER Metal2 ;
        RECT 101.080 54.200 101.480 54.600 ;
    END
  END S2MID[2]
  PIN S2MID[3]
    DIRECTION INPUT ;
    USE SIGNAL ;
    ANTENNAGATEAREA 0.180700 ;
    ANTENNADIFFAREA 2.015400 ;
    PORT
      LAYER Metal2 ;
        RECT 102.040 54.200 102.440 54.600 ;
    END
  END S2MID[3]
  PIN S2MID[4]
    DIRECTION INPUT ;
    USE SIGNAL ;
    ANTENNAGATEAREA 0.180700 ;
    ANTENNADIFFAREA 2.015400 ;
    PORT
      LAYER Metal2 ;
        RECT 103.000 54.200 103.400 54.600 ;
    END
  END S2MID[4]
  PIN S2MID[5]
    DIRECTION INPUT ;
    USE SIGNAL ;
    ANTENNAGATEAREA 0.180700 ;
    ANTENNADIFFAREA 2.015400 ;
    PORT
      LAYER Metal2 ;
        RECT 103.960 54.200 104.360 54.600 ;
    END
  END S2MID[5]
  PIN S2MID[6]
    DIRECTION INPUT ;
    USE SIGNAL ;
    ANTENNAGATEAREA 0.180700 ;
    ANTENNADIFFAREA 2.015400 ;
    PORT
      LAYER Metal2 ;
        RECT 104.920 54.200 105.320 54.600 ;
    END
  END S2MID[6]
  PIN S2MID[7]
    DIRECTION INPUT ;
    USE SIGNAL ;
    ANTENNAGATEAREA 0.180700 ;
    ANTENNADIFFAREA 2.015400 ;
    PORT
      LAYER Metal2 ;
        RECT 105.880 54.200 106.280 54.600 ;
    END
  END S2MID[7]
  PIN S4END[0]
    DIRECTION INPUT ;
    USE SIGNAL ;
    ANTENNAGATEAREA 0.180700 ;
    ANTENNADIFFAREA 2.015400 ;
    PORT
      LAYER Metal2 ;
        RECT 129.880 54.200 130.280 54.600 ;
    END
  END S4END[0]
  PIN S4END[10]
    DIRECTION INPUT ;
    USE SIGNAL ;
    ANTENNAGATEAREA 0.180700 ;
    ANTENNADIFFAREA 2.015400 ;
    PORT
      LAYER Metal2 ;
        RECT 139.480 54.200 139.880 54.600 ;
    END
  END S4END[10]
  PIN S4END[11]
    DIRECTION INPUT ;
    USE SIGNAL ;
    ANTENNAGATEAREA 0.180700 ;
    ANTENNADIFFAREA 2.015400 ;
    PORT
      LAYER Metal2 ;
        RECT 140.440 54.200 140.840 54.600 ;
    END
  END S4END[11]
  PIN S4END[12]
    DIRECTION INPUT ;
    USE SIGNAL ;
    ANTENNAGATEAREA 0.180700 ;
    ANTENNADIFFAREA 2.015400 ;
    PORT
      LAYER Metal2 ;
        RECT 141.400 54.200 141.800 54.600 ;
    END
  END S4END[12]
  PIN S4END[13]
    DIRECTION INPUT ;
    USE SIGNAL ;
    ANTENNAGATEAREA 0.180700 ;
    ANTENNADIFFAREA 2.015400 ;
    PORT
      LAYER Metal2 ;
        RECT 142.360 54.200 142.760 54.600 ;
    END
  END S4END[13]
  PIN S4END[14]
    DIRECTION INPUT ;
    USE SIGNAL ;
    ANTENNAGATEAREA 0.180700 ;
    ANTENNADIFFAREA 2.015400 ;
    PORT
      LAYER Metal2 ;
        RECT 143.320 54.200 143.720 54.600 ;
    END
  END S4END[14]
  PIN S4END[15]
    DIRECTION INPUT ;
    USE SIGNAL ;
    ANTENNAGATEAREA 0.180700 ;
    ANTENNADIFFAREA 2.015400 ;
    PORT
      LAYER Metal2 ;
        RECT 144.280 54.200 144.680 54.600 ;
    END
  END S4END[15]
  PIN S4END[1]
    DIRECTION INPUT ;
    USE SIGNAL ;
    ANTENNAGATEAREA 0.180700 ;
    ANTENNADIFFAREA 2.015400 ;
    PORT
      LAYER Metal2 ;
        RECT 130.840 54.200 131.240 54.600 ;
    END
  END S4END[1]
  PIN S4END[2]
    DIRECTION INPUT ;
    USE SIGNAL ;
    ANTENNAGATEAREA 0.180700 ;
    ANTENNADIFFAREA 2.015400 ;
    PORT
      LAYER Metal2 ;
        RECT 131.800 54.200 132.200 54.600 ;
    END
  END S4END[2]
  PIN S4END[3]
    DIRECTION INPUT ;
    USE SIGNAL ;
    ANTENNAGATEAREA 0.180700 ;
    ANTENNADIFFAREA 2.015400 ;
    PORT
      LAYER Metal2 ;
        RECT 132.760 54.200 133.160 54.600 ;
    END
  END S4END[3]
  PIN S4END[4]
    DIRECTION INPUT ;
    USE SIGNAL ;
    ANTENNAGATEAREA 0.180700 ;
    ANTENNADIFFAREA 2.015400 ;
    PORT
      LAYER Metal2 ;
        RECT 133.720 54.200 134.120 54.600 ;
    END
  END S4END[4]
  PIN S4END[5]
    DIRECTION INPUT ;
    USE SIGNAL ;
    ANTENNAGATEAREA 0.180700 ;
    ANTENNADIFFAREA 2.015400 ;
    PORT
      LAYER Metal2 ;
        RECT 134.680 54.200 135.080 54.600 ;
    END
  END S4END[5]
  PIN S4END[6]
    DIRECTION INPUT ;
    USE SIGNAL ;
    ANTENNAGATEAREA 0.180700 ;
    ANTENNADIFFAREA 2.015400 ;
    PORT
      LAYER Metal2 ;
        RECT 135.640 54.200 136.040 54.600 ;
    END
  END S4END[6]
  PIN S4END[7]
    DIRECTION INPUT ;
    USE SIGNAL ;
    ANTENNAGATEAREA 0.180700 ;
    ANTENNADIFFAREA 2.015400 ;
    PORT
      LAYER Metal2 ;
        RECT 136.600 54.200 137.000 54.600 ;
    END
  END S4END[7]
  PIN S4END[8]
    DIRECTION INPUT ;
    USE SIGNAL ;
    ANTENNAGATEAREA 0.180700 ;
    ANTENNADIFFAREA 2.015400 ;
    PORT
      LAYER Metal2 ;
        RECT 137.560 54.200 137.960 54.600 ;
    END
  END S4END[8]
  PIN S4END[9]
    DIRECTION INPUT ;
    USE SIGNAL ;
    ANTENNAGATEAREA 0.180700 ;
    ANTENNADIFFAREA 2.015400 ;
    PORT
      LAYER Metal2 ;
        RECT 138.520 54.200 138.920 54.600 ;
    END
  END S4END[9]
  PIN SS4END[0]
    DIRECTION INPUT ;
    USE SIGNAL ;
    ANTENNAGATEAREA 0.180700 ;
    ANTENNADIFFAREA 2.015400 ;
    PORT
      LAYER Metal2 ;
        RECT 157.720 54.200 158.120 54.600 ;
    END
  END SS4END[0]
  PIN SS4END[10]
    DIRECTION INPUT ;
    USE SIGNAL ;
    ANTENNAGATEAREA 0.180700 ;
    ANTENNADIFFAREA 2.015400 ;
    PORT
      LAYER Metal2 ;
        RECT 167.320 54.200 167.720 54.600 ;
    END
  END SS4END[10]
  PIN SS4END[11]
    DIRECTION INPUT ;
    USE SIGNAL ;
    ANTENNAGATEAREA 0.180700 ;
    ANTENNADIFFAREA 2.015400 ;
    PORT
      LAYER Metal2 ;
        RECT 168.280 54.200 168.680 54.600 ;
    END
  END SS4END[11]
  PIN SS4END[12]
    DIRECTION INPUT ;
    USE SIGNAL ;
    ANTENNAGATEAREA 0.180700 ;
    ANTENNADIFFAREA 2.015400 ;
    PORT
      LAYER Metal2 ;
        RECT 169.240 54.200 169.640 54.600 ;
    END
  END SS4END[12]
  PIN SS4END[13]
    DIRECTION INPUT ;
    USE SIGNAL ;
    ANTENNAGATEAREA 0.180700 ;
    ANTENNADIFFAREA 2.015400 ;
    PORT
      LAYER Metal2 ;
        RECT 170.200 54.200 170.600 54.600 ;
    END
  END SS4END[13]
  PIN SS4END[14]
    DIRECTION INPUT ;
    USE SIGNAL ;
    ANTENNAGATEAREA 0.180700 ;
    ANTENNADIFFAREA 2.015400 ;
    PORT
      LAYER Metal2 ;
        RECT 171.160 54.200 171.560 54.600 ;
    END
  END SS4END[14]
  PIN SS4END[15]
    DIRECTION INPUT ;
    USE SIGNAL ;
    ANTENNAGATEAREA 0.180700 ;
    ANTENNADIFFAREA 2.015400 ;
    PORT
      LAYER Metal2 ;
        RECT 172.120 54.200 172.520 54.600 ;
    END
  END SS4END[15]
  PIN SS4END[1]
    DIRECTION INPUT ;
    USE SIGNAL ;
    ANTENNAGATEAREA 0.180700 ;
    ANTENNADIFFAREA 2.015400 ;
    PORT
      LAYER Metal2 ;
        RECT 158.680 54.200 159.080 54.600 ;
    END
  END SS4END[1]
  PIN SS4END[2]
    DIRECTION INPUT ;
    USE SIGNAL ;
    ANTENNAGATEAREA 0.180700 ;
    ANTENNADIFFAREA 2.015400 ;
    PORT
      LAYER Metal2 ;
        RECT 159.640 54.200 160.040 54.600 ;
    END
  END SS4END[2]
  PIN SS4END[3]
    DIRECTION INPUT ;
    USE SIGNAL ;
    ANTENNAGATEAREA 0.180700 ;
    ANTENNADIFFAREA 2.015400 ;
    PORT
      LAYER Metal2 ;
        RECT 160.600 54.200 161.000 54.600 ;
    END
  END SS4END[3]
  PIN SS4END[4]
    DIRECTION INPUT ;
    USE SIGNAL ;
    ANTENNAGATEAREA 0.180700 ;
    ANTENNADIFFAREA 2.015400 ;
    PORT
      LAYER Metal2 ;
        RECT 161.560 54.200 161.960 54.600 ;
    END
  END SS4END[4]
  PIN SS4END[5]
    DIRECTION INPUT ;
    USE SIGNAL ;
    ANTENNAGATEAREA 0.180700 ;
    ANTENNADIFFAREA 2.015400 ;
    PORT
      LAYER Metal2 ;
        RECT 162.520 54.200 162.920 54.600 ;
    END
  END SS4END[5]
  PIN SS4END[6]
    DIRECTION INPUT ;
    USE SIGNAL ;
    ANTENNAGATEAREA 0.180700 ;
    ANTENNADIFFAREA 2.015400 ;
    PORT
      LAYER Metal2 ;
        RECT 163.480 54.200 163.880 54.600 ;
    END
  END SS4END[6]
  PIN SS4END[7]
    DIRECTION INPUT ;
    USE SIGNAL ;
    ANTENNAGATEAREA 0.180700 ;
    ANTENNADIFFAREA 2.015400 ;
    PORT
      LAYER Metal2 ;
        RECT 164.440 54.200 164.840 54.600 ;
    END
  END SS4END[7]
  PIN SS4END[8]
    DIRECTION INPUT ;
    USE SIGNAL ;
    ANTENNAGATEAREA 0.180700 ;
    ANTENNADIFFAREA 2.015400 ;
    PORT
      LAYER Metal2 ;
        RECT 165.400 54.200 165.800 54.600 ;
    END
  END SS4END[8]
  PIN SS4END[9]
    DIRECTION INPUT ;
    USE SIGNAL ;
    ANTENNAGATEAREA 0.180700 ;
    ANTENNADIFFAREA 2.015400 ;
    PORT
      LAYER Metal2 ;
        RECT 166.360 54.200 166.760 54.600 ;
    END
  END SS4END[9]
  PIN UserCLK
    DIRECTION INPUT ;
    USE SIGNAL ;
    ANTENNAGATEAREA 0.725400 ;
    PORT
      LAYER Metal3 ;
        RECT 0.000 1.060 0.400 1.460 ;
    END
  END UserCLK
  PIN UserCLKo
    DIRECTION OUTPUT ;
    USE SIGNAL ;
    ANTENNADIFFAREA 2.724000 ;
    PORT
      LAYER Metal3 ;
        RECT 215.600 1.060 216.000 1.460 ;
    END
  END UserCLKo
  PIN VGND
    DIRECTION INOUT ;
    USE GROUND ;
    PORT
      LAYER Metal4 ;
        RECT 21.580 0.000 23.780 54.600 ;
    END
    PORT
      LAYER Metal4 ;
        RECT 97.180 0.000 99.380 54.600 ;
    END
    PORT
      LAYER Metal4 ;
        RECT 172.780 0.000 174.980 54.600 ;
    END
  END VGND
  PIN VPWR
    DIRECTION INOUT ;
    USE POWER ;
    PORT
      LAYER Metal4 ;
        RECT 15.380 0.000 17.580 54.600 ;
    END
    PORT
      LAYER Metal4 ;
        RECT 90.980 0.000 93.180 54.600 ;
    END
    PORT
      LAYER Metal4 ;
        RECT 166.580 0.000 168.780 54.600 ;
    END
  END VPWR
  OBS
      LAYER GatPoly ;
        RECT 2.880 3.630 213.120 49.290 ;
      LAYER Metal1 ;
        RECT 2.880 3.560 213.120 49.360 ;
      LAYER Metal2 ;
        RECT 2.810 53.990 2.950 54.325 ;
        RECT 3.770 53.990 3.910 54.325 ;
        RECT 4.730 53.990 4.870 54.325 ;
        RECT 5.690 53.990 10.630 54.325 ;
        RECT 11.450 53.990 11.590 54.325 ;
        RECT 12.410 53.990 12.550 54.325 ;
        RECT 13.370 53.990 13.510 54.325 ;
        RECT 14.330 53.990 14.470 54.325 ;
        RECT 15.290 53.990 15.430 54.325 ;
        RECT 16.250 53.990 16.390 54.325 ;
        RECT 17.210 53.990 17.350 54.325 ;
        RECT 18.170 53.990 24.070 54.325 ;
        RECT 24.890 53.990 25.030 54.325 ;
        RECT 25.850 53.990 25.990 54.325 ;
        RECT 26.810 53.990 26.950 54.325 ;
        RECT 27.770 53.990 27.910 54.325 ;
        RECT 28.730 53.990 28.870 54.325 ;
        RECT 29.690 53.990 29.830 54.325 ;
        RECT 30.650 53.990 30.790 54.325 ;
        RECT 31.610 53.990 40.390 54.325 ;
        RECT 41.210 53.990 41.350 54.325 ;
        RECT 42.170 53.990 42.310 54.325 ;
        RECT 43.130 53.990 43.270 54.325 ;
        RECT 44.090 53.990 44.230 54.325 ;
        RECT 45.050 53.990 45.190 54.325 ;
        RECT 46.010 53.990 46.150 54.325 ;
        RECT 46.970 53.990 47.110 54.325 ;
        RECT 47.930 53.990 48.070 54.325 ;
        RECT 48.890 53.990 49.030 54.325 ;
        RECT 49.850 53.990 49.990 54.325 ;
        RECT 50.810 53.990 50.950 54.325 ;
        RECT 51.770 53.990 51.910 54.325 ;
        RECT 52.730 53.990 52.870 54.325 ;
        RECT 53.690 53.990 53.830 54.325 ;
        RECT 54.650 53.990 54.790 54.325 ;
        RECT 55.610 53.990 68.230 54.325 ;
        RECT 69.050 53.990 69.190 54.325 ;
        RECT 70.010 53.990 70.150 54.325 ;
        RECT 70.970 53.990 71.110 54.325 ;
        RECT 71.930 53.990 72.070 54.325 ;
        RECT 72.890 53.990 73.030 54.325 ;
        RECT 73.850 53.990 73.990 54.325 ;
        RECT 74.810 53.990 74.950 54.325 ;
        RECT 75.770 53.990 75.910 54.325 ;
        RECT 76.730 53.990 76.870 54.325 ;
        RECT 77.690 53.990 77.830 54.325 ;
        RECT 78.650 53.990 78.790 54.325 ;
        RECT 79.610 53.990 79.750 54.325 ;
        RECT 80.570 53.990 80.710 54.325 ;
        RECT 81.530 53.990 81.670 54.325 ;
        RECT 82.490 53.990 82.630 54.325 ;
        RECT 83.450 53.990 90.310 54.325 ;
        RECT 91.130 53.990 91.270 54.325 ;
        RECT 92.090 53.990 92.230 54.325 ;
        RECT 93.050 53.990 93.190 54.325 ;
        RECT 94.010 53.990 98.950 54.325 ;
        RECT 99.770 53.990 99.910 54.325 ;
        RECT 100.730 53.990 100.870 54.325 ;
        RECT 101.690 53.990 101.830 54.325 ;
        RECT 102.650 53.990 102.790 54.325 ;
        RECT 103.610 53.990 103.750 54.325 ;
        RECT 104.570 53.990 104.710 54.325 ;
        RECT 105.530 53.990 105.670 54.325 ;
        RECT 106.490 53.990 113.350 54.325 ;
        RECT 114.170 53.990 114.310 54.325 ;
        RECT 115.130 53.990 115.270 54.325 ;
        RECT 116.090 53.990 116.230 54.325 ;
        RECT 117.050 53.990 117.190 54.325 ;
        RECT 118.010 53.990 118.150 54.325 ;
        RECT 118.970 53.990 119.110 54.325 ;
        RECT 119.930 53.990 120.070 54.325 ;
        RECT 120.890 53.990 129.670 54.325 ;
        RECT 130.490 53.990 130.630 54.325 ;
        RECT 131.450 53.990 131.590 54.325 ;
        RECT 132.410 53.990 132.550 54.325 ;
        RECT 133.370 53.990 133.510 54.325 ;
        RECT 134.330 53.990 134.470 54.325 ;
        RECT 135.290 53.990 135.430 54.325 ;
        RECT 136.250 53.990 136.390 54.325 ;
        RECT 137.210 53.990 137.350 54.325 ;
        RECT 138.170 53.990 138.310 54.325 ;
        RECT 139.130 53.990 139.270 54.325 ;
        RECT 140.090 53.990 140.230 54.325 ;
        RECT 141.050 53.990 141.190 54.325 ;
        RECT 142.010 53.990 142.150 54.325 ;
        RECT 142.970 53.990 143.110 54.325 ;
        RECT 143.930 53.990 144.070 54.325 ;
        RECT 144.890 53.990 157.510 54.325 ;
        RECT 158.330 53.990 158.470 54.325 ;
        RECT 159.290 53.990 159.430 54.325 ;
        RECT 160.250 53.990 160.390 54.325 ;
        RECT 161.210 53.990 161.350 54.325 ;
        RECT 162.170 53.990 162.310 54.325 ;
        RECT 163.130 53.990 163.270 54.325 ;
        RECT 164.090 53.990 164.230 54.325 ;
        RECT 165.050 53.990 165.190 54.325 ;
        RECT 166.010 53.990 166.150 54.325 ;
        RECT 166.970 53.990 167.110 54.325 ;
        RECT 167.930 53.990 168.070 54.325 ;
        RECT 168.890 53.990 169.030 54.325 ;
        RECT 169.850 53.990 169.990 54.325 ;
        RECT 170.810 53.990 170.950 54.325 ;
        RECT 171.770 53.990 171.910 54.325 ;
        RECT 172.730 53.990 179.590 54.325 ;
        RECT 180.410 53.990 189.190 54.325 ;
        RECT 190.010 53.990 190.150 54.325 ;
        RECT 190.970 53.990 191.110 54.325 ;
        RECT 191.930 53.990 192.070 54.325 ;
        RECT 192.890 53.990 193.030 54.325 ;
        RECT 193.850 53.990 193.990 54.325 ;
        RECT 194.810 53.990 194.950 54.325 ;
        RECT 195.770 53.990 195.910 54.325 ;
        RECT 196.730 53.990 196.870 54.325 ;
        RECT 197.690 53.990 197.830 54.325 ;
        RECT 198.650 53.990 198.790 54.325 ;
        RECT 199.610 53.990 199.750 54.325 ;
        RECT 200.570 53.990 200.710 54.325 ;
        RECT 201.530 53.990 201.670 54.325 ;
        RECT 202.490 53.990 202.630 54.325 ;
        RECT 203.450 53.990 203.590 54.325 ;
        RECT 204.410 53.990 204.550 54.325 ;
        RECT 205.370 53.990 205.510 54.325 ;
        RECT 206.330 53.990 206.470 54.325 ;
        RECT 207.290 53.990 207.430 54.325 ;
        RECT 208.250 53.990 215.625 54.325 ;
        RECT 2.295 0.610 215.625 53.990 ;
        RECT 2.295 0.275 7.750 0.610 ;
        RECT 8.570 0.275 18.310 0.610 ;
        RECT 19.130 0.275 28.870 0.610 ;
        RECT 29.690 0.275 39.430 0.610 ;
        RECT 40.250 0.275 49.990 0.610 ;
        RECT 50.810 0.275 60.550 0.610 ;
        RECT 61.370 0.275 71.110 0.610 ;
        RECT 71.930 0.275 81.670 0.610 ;
        RECT 82.490 0.275 92.230 0.610 ;
        RECT 93.050 0.275 102.790 0.610 ;
        RECT 103.610 0.275 113.350 0.610 ;
        RECT 114.170 0.275 123.910 0.610 ;
        RECT 124.730 0.275 134.470 0.610 ;
        RECT 135.290 0.275 145.030 0.610 ;
        RECT 145.850 0.275 155.590 0.610 ;
        RECT 156.410 0.275 166.150 0.610 ;
        RECT 166.970 0.275 176.710 0.610 ;
        RECT 177.530 0.275 187.270 0.610 ;
        RECT 188.090 0.275 197.830 0.610 ;
        RECT 198.650 0.275 208.390 0.610 ;
        RECT 209.210 0.275 215.625 0.610 ;
      LAYER Metal3 ;
        RECT 0.400 41.990 215.665 54.285 ;
        RECT 0.610 41.170 215.390 41.990 ;
        RECT 0.400 41.150 215.665 41.170 ;
        RECT 0.610 40.330 215.390 41.150 ;
        RECT 0.400 40.310 215.665 40.330 ;
        RECT 0.610 39.490 215.390 40.310 ;
        RECT 0.400 39.470 215.665 39.490 ;
        RECT 0.610 38.650 215.390 39.470 ;
        RECT 0.400 38.630 215.665 38.650 ;
        RECT 0.610 37.810 215.390 38.630 ;
        RECT 0.400 37.790 215.665 37.810 ;
        RECT 0.610 36.970 215.390 37.790 ;
        RECT 0.400 36.950 215.665 36.970 ;
        RECT 0.610 36.130 215.390 36.950 ;
        RECT 0.400 36.110 215.665 36.130 ;
        RECT 0.610 35.290 215.390 36.110 ;
        RECT 0.400 35.270 215.665 35.290 ;
        RECT 0.610 34.450 215.390 35.270 ;
        RECT 0.400 34.430 215.665 34.450 ;
        RECT 0.610 33.610 215.390 34.430 ;
        RECT 0.400 33.590 215.665 33.610 ;
        RECT 0.610 32.770 215.390 33.590 ;
        RECT 0.400 32.750 215.665 32.770 ;
        RECT 0.610 31.930 215.390 32.750 ;
        RECT 0.400 31.910 215.665 31.930 ;
        RECT 0.610 31.090 215.390 31.910 ;
        RECT 0.400 31.070 215.665 31.090 ;
        RECT 0.610 30.250 215.390 31.070 ;
        RECT 0.400 30.230 215.665 30.250 ;
        RECT 0.610 29.410 215.390 30.230 ;
        RECT 0.400 29.390 215.665 29.410 ;
        RECT 0.610 28.570 215.390 29.390 ;
        RECT 0.400 28.550 215.665 28.570 ;
        RECT 0.610 27.730 215.390 28.550 ;
        RECT 0.400 27.710 215.665 27.730 ;
        RECT 0.610 26.890 215.390 27.710 ;
        RECT 0.400 26.870 215.665 26.890 ;
        RECT 0.610 26.050 215.390 26.870 ;
        RECT 0.400 26.030 215.665 26.050 ;
        RECT 0.610 25.210 215.390 26.030 ;
        RECT 0.400 25.190 215.665 25.210 ;
        RECT 0.610 24.370 215.390 25.190 ;
        RECT 0.400 24.350 215.665 24.370 ;
        RECT 0.610 23.530 215.390 24.350 ;
        RECT 0.400 23.510 215.665 23.530 ;
        RECT 0.610 22.690 215.390 23.510 ;
        RECT 0.400 22.670 215.665 22.690 ;
        RECT 0.610 21.850 215.390 22.670 ;
        RECT 0.400 21.830 215.665 21.850 ;
        RECT 0.610 21.010 215.390 21.830 ;
        RECT 0.400 20.990 215.665 21.010 ;
        RECT 0.610 20.170 215.390 20.990 ;
        RECT 0.400 20.150 215.665 20.170 ;
        RECT 0.610 19.330 215.390 20.150 ;
        RECT 0.400 19.310 215.665 19.330 ;
        RECT 0.610 18.490 215.390 19.310 ;
        RECT 0.400 18.470 215.665 18.490 ;
        RECT 0.610 17.650 215.390 18.470 ;
        RECT 0.400 17.630 215.665 17.650 ;
        RECT 0.610 16.810 215.390 17.630 ;
        RECT 0.400 16.790 215.665 16.810 ;
        RECT 0.610 15.970 215.390 16.790 ;
        RECT 0.400 15.950 215.665 15.970 ;
        RECT 0.610 15.130 215.390 15.950 ;
        RECT 0.400 1.670 215.665 15.130 ;
        RECT 0.610 0.850 215.390 1.670 ;
        RECT 0.400 0.320 215.665 0.850 ;
      LAYER Metal4 ;
        RECT 12.170 1.535 15.170 54.325 ;
        RECT 17.790 1.535 21.370 54.325 ;
        RECT 23.990 1.535 90.770 54.325 ;
        RECT 93.390 1.535 96.970 54.325 ;
        RECT 99.590 1.535 166.370 54.325 ;
        RECT 168.990 1.535 172.570 54.325 ;
        RECT 175.190 1.535 210.070 54.325 ;
      LAYER TopMetal1 ;
        RECT 11.660 5.380 210.580 45.780 ;
  END
END S_term_single
END LIBRARY

